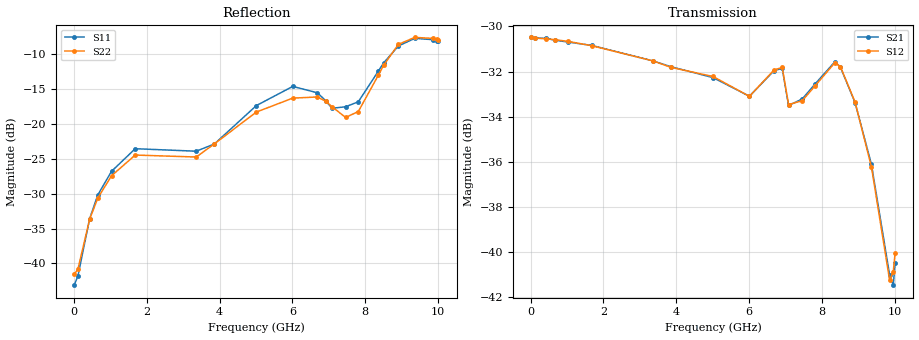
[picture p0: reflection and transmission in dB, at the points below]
! Device ID: PE43705
! Serial: 1
! Insertion: A
! Impedance: 50 ohm
! Temp: 25C
! VDD: 3.400V
! Attenuation Step: 29.50dB
#  Hz  S  RI  R  50
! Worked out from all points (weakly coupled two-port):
!   401 points, 10 MHz to 10.01 GHz, reference 50 ohm
!   highest |S21| = -30.48 dB at 10 MHz (marker M1); lowest = -41.5 dB at 9.96 GHz (marker M2)
!   lowest |S11| = -43.1 dB at 10 MHz (marker M3), VSWR 1.01, Z = 49.3 + j0.0485 ohm
!   |S11| at or under -10 dB: start of sweep to 8.693 GHz
!   |S22| runs from -41.7 to -7.5 dB; largest |S21 - S12| = 0.00065
!   S11 on the Smith chart (normalised r, x): 10 MHz: 0.99, +0.00; 7.46 GHz: 0.82, +0.16; 8.51 GHz: 0.82, +0.48; 9.36 GHz: 0.54, +0.48; 10.01 GHz: 0.48, +0.26
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1e7  -0.00698 0.000492  0.0299 -0.000121  0.0299 -8.24e-05  -0.00835 0.000455
1.1e8  -0.0066 0.00466  0.0298 -0.000863  0.0298 -0.000806  -0.00779 0.00463
4.35e8  -0.0117 0.0174  0.0296 -0.00315  0.0295 -0.00313  -0.0121 0.0169
6.6e8  -0.02 0.0237  0.0291 -0.00467  0.0292 -0.00461  -0.019 0.0225
1.035e9  -0.0371 0.0266  0.0283 -0.00718  0.0284 -0.00717  -0.0339 0.0255
1.685e9  -0.0642 0.0164  0.0265 -0.011  0.0265 -0.0109  -0.057 0.0177
3.36e9  -0.0635 0.0032  0.0191 -0.0184  0.0191 -0.0184  -0.0565 0.0121
3.86e9  -0.0668 0.026  0.0168 -0.0195  0.0169 -0.0193  -0.0666 0.0268
5.01e9  -0.1036 0.0863  0.0125 -0.0209  0.0126 -0.021  -0.1027 0.0644
6.01e9  -0.1556 0.1  0.00786 -0.0207  0.00809 -0.0206  -0.1304 0.0791
6.685e9  -0.1466 0.0791  0.00635 -0.0244  0.00637 -0.0245  -0.1371 0.0731
6.91e9  -0.1286 0.0704  0.00271 -0.0254  0.00278 -0.0255  -0.1257 0.0727
7.085e9  -0.1135 0.0613  0.000936 -0.0211  0.000933 -0.0212  -0.1079 0.0772
7.46e9  -0.0929 0.0941  0.00244 -0.0217  0.00248 -0.0215  -0.0722 0.0842
7.81e9  -0.0486 0.1351  0.00274 -0.0234  0.0025 -0.0232  -0.0478 0.1126
8.36e9  -0.0164 0.2375  -0.00571 -0.0258  -0.00559 -0.0257  -0.0365 0.2196
8.51e9  -0.0257 0.2721  -0.00851 -0.0242  -0.00817 -0.0244  -0.0455 0.2592
8.91e9  -0.0804 0.3512  -0.0118 -0.0179  -0.0119 -0.0179  -0.1067 0.3542
9.36e9  -0.1813 0.366  -0.0106 -0.0115  -0.0103 -0.0115  -0.1992 0.364
9.86e9  -0.2898 0.2749  -0.00338 -0.00822  -0.00307 -0.00809  -0.3167 0.2572
9.96e9  -0.3068 0.2445  -0.00166 -0.00828  -0.00154 -0.00892  -0.3359 0.2192
1.001e10  -0.3143 0.2277  -0.000932 -0.00939  -0.00102 -0.00989  -0.3465 0.1984
